VERSION 5.7 ;
  NOWIREEXTENSIONATPIN ON ;
  DIVIDERCHAR "/" ;
  BUSBITCHARS "[]" ;
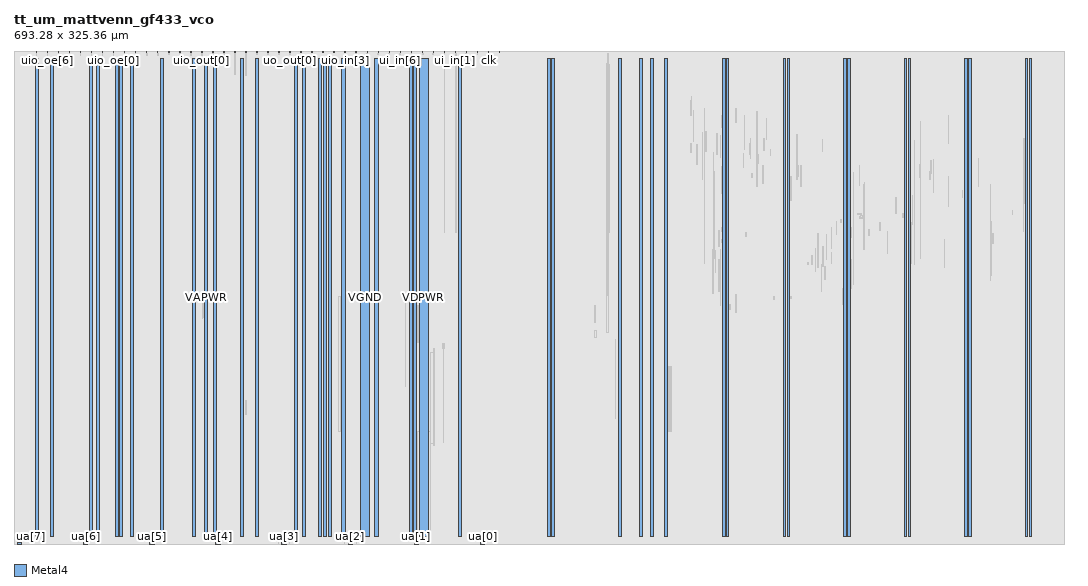
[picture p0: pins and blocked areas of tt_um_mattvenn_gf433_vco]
MACRO tt_um_mattvenn_gf433_vco
  CLASS BLOCK ;
  FOREIGN tt_um_mattvenn_gf433_vco ;
  ORIGIN 0.000 0.000 ;
  SIZE 693.280 BY 325.360 ;
  PIN clk
    DIRECTION INPUT ;
    USE SIGNAL ;
    PORT
      LAYER Metal4 ;
        RECT 313.170 324.360 313.470 325.360 ;
    END
  END clk
  PIN ena
    DIRECTION INPUT ;
    USE SIGNAL ;
    PORT
      LAYER Metal4 ;
        RECT 320.450 324.360 320.750 325.360 ;
    END
  END ena
  PIN rst_n
    DIRECTION INPUT ;
    USE SIGNAL ;
    PORT
      LAYER Metal4 ;
        RECT 305.890 324.360 306.190 325.360 ;
    END
  END rst_n
  PIN ua[0]
    DIRECTION INOUT ;
    USE SIGNAL ;
    PORT
      LAYER Metal4 ;
        RECT 307.900 0.000 310.900 1.000 ;
    END
  END ua[0]
  PIN ua[1]
    DIRECTION INOUT ;
    USE SIGNAL ;
    PORT
      LAYER Metal4 ;
        RECT 264.220 0.000 267.220 1.000 ;
    END
  END ua[1]
  PIN ua[2]
    DIRECTION INOUT ;
    USE SIGNAL ;
    PORT
      LAYER Metal4 ;
        RECT 220.540 0.000 223.540 1.000 ;
    END
  END ua[2]
  PIN ua[3]
    DIRECTION INOUT ;
    USE SIGNAL ;
    PORT
      LAYER Metal4 ;
        RECT 176.860 0.000 179.860 1.000 ;
    END
  END ua[3]
  PIN ua[4]
    DIRECTION INOUT ;
    USE SIGNAL ;
    PORT
      LAYER Metal4 ;
        RECT 133.180 0.000 136.180 1.000 ;
    END
  END ua[4]
  PIN ua[5]
    DIRECTION INOUT ;
    USE SIGNAL ;
    PORT
      LAYER Metal4 ;
        RECT 89.500 0.000 92.500 1.000 ;
    END
  END ua[5]
  PIN ua[6]
    DIRECTION INOUT ;
    USE SIGNAL ;
    PORT
      LAYER Metal4 ;
        RECT 45.820 0.000 48.820 1.000 ;
    END
  END ua[6]
  PIN ua[7]
    DIRECTION INOUT ;
    USE SIGNAL ;
    PORT
      LAYER Metal4 ;
        RECT 2.140 0.000 5.140 1.000 ;
    END
  END ua[7]
  PIN ui_in[0]
    DIRECTION INPUT ;
    USE SIGNAL ;
    PORT
      LAYER Metal4 ;
        RECT 298.610 324.360 298.910 325.360 ;
    END
  END ui_in[0]
  PIN ui_in[1]
    DIRECTION INPUT ;
    USE SIGNAL ;
    PORT
      LAYER Metal4 ;
        RECT 291.330 324.360 291.630 325.360 ;
    END
  END ui_in[1]
  PIN ui_in[2]
    DIRECTION INPUT ;
    USE SIGNAL ;
    PORT
      LAYER Metal4 ;
        RECT 284.050 324.360 284.350 325.360 ;
    END
  END ui_in[2]
  PIN ui_in[3]
    DIRECTION INPUT ;
    USE SIGNAL ;
    PORT
      LAYER Metal4 ;
        RECT 276.770 324.360 277.070 325.360 ;
    END
  END ui_in[3]
  PIN ui_in[4]
    DIRECTION INPUT ;
    USE SIGNAL ;
    PORT
      LAYER Metal4 ;
        RECT 269.490 324.360 269.790 325.360 ;
    END
  END ui_in[4]
  PIN ui_in[5]
    DIRECTION INPUT ;
    USE SIGNAL ;
    PORT
      LAYER Metal4 ;
        RECT 262.210 324.360 262.510 325.360 ;
    END
  END ui_in[5]
  PIN ui_in[6]
    DIRECTION INPUT ;
    USE SIGNAL ;
    PORT
      LAYER Metal4 ;
        RECT 254.930 324.360 255.230 325.360 ;
    END
  END ui_in[6]
  PIN ui_in[7]
    DIRECTION INPUT ;
    USE SIGNAL ;
    PORT
      LAYER Metal4 ;
        RECT 247.650 324.360 247.950 325.360 ;
    END
  END ui_in[7]
  PIN uio_in[0]
    DIRECTION INPUT ;
    USE SIGNAL ;
    PORT
      LAYER Metal4 ;
        RECT 240.370 324.360 240.670 325.360 ;
    END
  END uio_in[0]
  PIN uio_in[1]
    DIRECTION INPUT ;
    USE SIGNAL ;
    PORT
      LAYER Metal4 ;
        RECT 233.090 324.360 233.390 325.360 ;
    END
  END uio_in[1]
  PIN uio_in[2]
    DIRECTION INPUT ;
    USE SIGNAL ;
    PORT
      LAYER Metal4 ;
        RECT 225.810 324.360 226.110 325.360 ;
    END
  END uio_in[2]
  PIN uio_in[3]
    DIRECTION INPUT ;
    USE SIGNAL ;
    PORT
      LAYER Metal4 ;
        RECT 218.530 324.360 218.830 325.360 ;
    END
  END uio_in[3]
  PIN uio_in[4]
    DIRECTION INPUT ;
    USE SIGNAL ;
    PORT
      LAYER Metal4 ;
        RECT 211.250 324.360 211.550 325.360 ;
    END
  END uio_in[4]
  PIN uio_in[5]
    DIRECTION INPUT ;
    USE SIGNAL ;
    PORT
      LAYER Metal4 ;
        RECT 203.970 324.360 204.270 325.360 ;
    END
  END uio_in[5]
  PIN uio_in[6]
    DIRECTION INPUT ;
    USE SIGNAL ;
    PORT
      LAYER Metal4 ;
        RECT 196.690 324.360 196.990 325.360 ;
    END
  END uio_in[6]
  PIN uio_in[7]
    DIRECTION INPUT ;
    USE SIGNAL ;
    PORT
      LAYER Metal4 ;
        RECT 189.410 324.360 189.710 325.360 ;
    END
  END uio_in[7]
  PIN uio_oe[0]
    DIRECTION OUTPUT ;
    USE SIGNAL ;
    PORT
      LAYER Metal4 ;
        RECT 65.650 324.360 65.950 325.360 ;
    END
  END uio_oe[0]
  PIN uio_oe[1]
    DIRECTION OUTPUT ;
    USE SIGNAL ;
    PORT
      LAYER Metal4 ;
        RECT 58.370 324.360 58.670 325.360 ;
    END
  END uio_oe[1]
  PIN uio_oe[2]
    DIRECTION OUTPUT ;
    USE SIGNAL ;
    PORT
      LAYER Metal4 ;
        RECT 51.090 324.360 51.390 325.360 ;
    END
  END uio_oe[2]
  PIN uio_oe[3]
    DIRECTION OUTPUT ;
    USE SIGNAL ;
    PORT
      LAYER Metal4 ;
        RECT 43.810 324.360 44.110 325.360 ;
    END
  END uio_oe[3]
  PIN uio_oe[4]
    DIRECTION OUTPUT ;
    USE SIGNAL ;
    PORT
      LAYER Metal4 ;
        RECT 36.530 324.360 36.830 325.360 ;
    END
  END uio_oe[4]
  PIN uio_oe[5]
    DIRECTION OUTPUT ;
    USE SIGNAL ;
    PORT
      LAYER Metal4 ;
        RECT 29.250 324.360 29.550 325.360 ;
    END
  END uio_oe[5]
  PIN uio_oe[6]
    DIRECTION OUTPUT ;
    USE SIGNAL ;
    PORT
      LAYER Metal4 ;
        RECT 21.970 324.360 22.270 325.360 ;
    END
  END uio_oe[6]
  PIN uio_oe[7]
    DIRECTION OUTPUT ;
    USE SIGNAL ;
    PORT
      LAYER Metal4 ;
        RECT 14.690 324.360 14.990 325.360 ;
    END
  END uio_oe[7]
  PIN uio_out[0]
    DIRECTION OUTPUT ;
    USE SIGNAL ;
    PORT
      LAYER Metal4 ;
        RECT 123.890 324.360 124.190 325.360 ;
    END
  END uio_out[0]
  PIN uio_out[1]
    DIRECTION OUTPUT ;
    USE SIGNAL ;
    PORT
      LAYER Metal4 ;
        RECT 116.610 324.360 116.910 325.360 ;
    END
  END uio_out[1]
  PIN uio_out[2]
    DIRECTION OUTPUT ;
    USE SIGNAL ;
    PORT
      LAYER Metal4 ;
        RECT 109.330 324.360 109.630 325.360 ;
    END
  END uio_out[2]
  PIN uio_out[3]
    DIRECTION OUTPUT ;
    USE SIGNAL ;
    PORT
      LAYER Metal4 ;
        RECT 102.050 324.360 102.350 325.360 ;
    END
  END uio_out[3]
  PIN uio_out[4]
    DIRECTION OUTPUT ;
    USE SIGNAL ;
    PORT
      LAYER Metal4 ;
        RECT 94.770 324.360 95.070 325.360 ;
    END
  END uio_out[4]
  PIN uio_out[5]
    DIRECTION OUTPUT ;
    USE SIGNAL ;
    PORT
      LAYER Metal4 ;
        RECT 87.490 324.360 87.790 325.360 ;
    END
  END uio_out[5]
  PIN uio_out[6]
    DIRECTION OUTPUT ;
    USE SIGNAL ;
    PORT
      LAYER Metal4 ;
        RECT 80.210 324.360 80.510 325.360 ;
    END
  END uio_out[6]
  PIN uio_out[7]
    DIRECTION OUTPUT ;
    USE SIGNAL ;
    PORT
      LAYER Metal4 ;
        RECT 72.930 324.360 73.230 325.360 ;
    END
  END uio_out[7]
  PIN uo_out[0]
    DIRECTION OUTPUT ;
    USE SIGNAL ;
    PORT
      LAYER Metal4 ;
        RECT 182.130 324.360 182.430 325.360 ;
    END
  END uo_out[0]
  PIN uo_out[1]
    DIRECTION OUTPUT ;
    USE SIGNAL ;
    PORT
      LAYER Metal4 ;
        RECT 174.850 324.360 175.150 325.360 ;
    END
  END uo_out[1]
  PIN uo_out[2]
    DIRECTION OUTPUT ;
    USE SIGNAL ;
    PORT
      LAYER Metal4 ;
        RECT 167.570 324.360 167.870 325.360 ;
    END
  END uo_out[2]
  PIN uo_out[3]
    DIRECTION OUTPUT ;
    USE SIGNAL ;
    PORT
      LAYER Metal4 ;
        RECT 160.290 324.360 160.590 325.360 ;
    END
  END uo_out[3]
  PIN uo_out[4]
    DIRECTION OUTPUT ;
    USE SIGNAL ;
    PORT
      LAYER Metal4 ;
        RECT 153.010 324.360 153.310 325.360 ;
    END
  END uo_out[4]
  PIN uo_out[5]
    DIRECTION OUTPUT ;
    USE SIGNAL ;
    PORT
      LAYER Metal4 ;
        RECT 145.730 324.360 146.030 325.360 ;
    END
  END uo_out[5]
  PIN uo_out[6]
    DIRECTION OUTPUT ;
    USE SIGNAL ;
    PORT
      LAYER Metal4 ;
        RECT 138.450 324.360 138.750 325.360 ;
    END
  END uo_out[6]
  PIN uo_out[7]
    DIRECTION OUTPUT ;
    USE SIGNAL ;
    PORT
      LAYER Metal4 ;
        RECT 131.170 324.360 131.470 325.360 ;
    END
  END uo_out[7]
  PIN VDPWR
    DIRECTION INOUT ;
    USE POWER ;
    PORT
      LAYER Metal4 ;
        RECT 267.500 5.000 273.500 320.360 ;
    END
    PORT
      LAYER Metal4 ;
        RECT 470.480 5.000 472.080 320.360 ;
    END
    PORT
      LAYER Metal4 ;
        RECT 510.480 5.000 512.080 320.360 ;
    END
    PORT
      LAYER Metal4 ;
        RECT 550.480 5.000 552.080 320.360 ;
    END
    PORT
      LAYER Metal4 ;
        RECT 590.480 5.000 592.080 320.360 ;
    END
    PORT
      LAYER Metal4 ;
        RECT 630.480 5.000 632.080 320.360 ;
    END
    PORT
      LAYER Metal4 ;
        RECT 670.480 5.000 672.080 320.360 ;
    END
  END VDPWR
  PIN VAPWR
    DIRECTION INOUT ;
    USE POWER ;
    PORT
      LAYER Metal4 ;
        RECT 49.520 5.000 51.520 320.360 ;
    END
    PORT
      LAYER Metal4 ;
        RECT 66.880 5.000 68.880 320.360 ;
    END
    PORT
      LAYER Metal4 ;
        RECT 76.700 5.000 78.700 320.360 ;
    END
    PORT
      LAYER Metal4 ;
        RECT 118.100 5.000 120.100 320.360 ;
    END
    PORT
      LAYER Metal4 ;
        RECT 126.020 5.000 128.020 320.360 ;
    END
    PORT
      LAYER Metal4 ;
        RECT 185.360 5.000 187.360 320.360 ;
    END
    PORT
      LAYER Metal4 ;
        RECT 201.330 5.000 203.330 320.360 ;
    END
    PORT
      LAYER Metal4 ;
        RECT 207.410 5.000 209.410 320.360 ;
    END
    PORT
      LAYER Metal4 ;
        RECT 216.550 5.000 218.550 320.360 ;
    END
    PORT
      LAYER Metal4 ;
        RECT 260.900 5.000 262.900 320.360 ;
    END
    PORT
      LAYER Metal4 ;
        RECT 293.610 5.000 295.610 320.360 ;
    END
    PORT
      LAYER Metal4 ;
        RECT 351.990 5.000 353.990 320.360 ;
    END
    PORT
      LAYER Metal4 ;
        RECT 399.100 5.000 401.100 320.360 ;
    END
    PORT
      LAYER Metal4 ;
        RECT 429.480 5.000 431.480 320.360 ;
    END
  END VAPWR
  PIN VGND
    DIRECTION INOUT ;
    USE GROUND ;
    PORT
      LAYER Metal4 ;
        RECT 14.010 5.000 16.010 320.360 ;
    END
    PORT
      LAYER Metal4 ;
        RECT 23.790 5.000 25.790 320.360 ;
    END
    PORT
      LAYER Metal4 ;
        RECT 54.440 5.000 56.440 320.360 ;
    END
    PORT
      LAYER Metal4 ;
        RECT 69.880 5.000 71.880 320.360 ;
    END
    PORT
      LAYER Metal4 ;
        RECT 97.010 5.000 99.010 320.360 ;
    END
    PORT
      LAYER Metal4 ;
        RECT 131.670 5.000 133.670 320.360 ;
    END
    PORT
      LAYER Metal4 ;
        RECT 149.830 5.000 151.830 320.360 ;
    END
    PORT
      LAYER Metal4 ;
        RECT 159.630 5.000 161.630 320.360 ;
    END
    PORT
      LAYER Metal4 ;
        RECT 190.270 5.000 192.270 320.360 ;
    END
    PORT
      LAYER Metal4 ;
        RECT 204.330 5.000 206.330 320.360 ;
    END
    PORT
      LAYER Metal4 ;
        RECT 228.530 5.000 234.530 320.360 ;
    END
    PORT
      LAYER Metal4 ;
        RECT 238.350 5.000 240.350 320.360 ;
    END
    PORT
      LAYER Metal4 ;
        RECT 263.960 5.000 265.960 320.360 ;
    END
    PORT
      LAYER Metal4 ;
        RECT 354.990 5.000 356.990 320.360 ;
    END
    PORT
      LAYER Metal4 ;
        RECT 412.670 5.000 414.670 320.360 ;
    END
    PORT
      LAYER Metal4 ;
        RECT 420.510 5.000 422.510 320.360 ;
    END
    PORT
      LAYER Metal4 ;
        RECT 467.880 5.000 469.480 320.360 ;
    END
    PORT
      LAYER Metal4 ;
        RECT 507.880 5.000 509.480 320.360 ;
    END
    PORT
      LAYER Metal4 ;
        RECT 547.880 5.000 549.480 320.360 ;
    END
    PORT
      LAYER Metal4 ;
        RECT 587.880 5.000 589.480 320.360 ;
    END
    PORT
      LAYER Metal4 ;
        RECT 627.880 5.000 629.480 320.360 ;
    END
    PORT
      LAYER Metal4 ;
        RECT 667.880 5.000 669.480 320.360 ;
    END
  END VGND
  OBS
    LAYER Metal1 ;
      RECT 0.000 0.000 693.280 325.360 ;
    LAYER Metal2 ;
      RECT 0.000 0.000 693.280 325.360 ;
    LAYER Metal3 ;
      RECT 0.000 0.000 693.280 325.360 ;
    LAYER Metal4 ;
      RECT 501.660 161.290 501.940 163.350 ;
      RECT 512.860 161.850 513.140 163.350 ;
      RECT 214.010 74.610 215.750 163.390 ;
      RECT 476.460 152.890 476.740 164.470 ;
      RECT 547.020 157.930 547.300 168.950 ;
      RECT 466.380 157.370 466.660 194.150 ;
      RECT 391.490 139.890 392.550 317.070 ;
      RECT 533.020 166.890 533.300 184.630 ;
      RECT 524.060 184.250 524.340 185.750 ;
      RECT 465.260 166.890 465.540 187.990 ;
      RECT 552.620 168.570 552.900 187.990 ;
      RECT 526.860 184.250 527.140 190.790 ;
      RECT 539.740 185.370 540.020 192.470 ;
      RECT 463.020 179.210 463.300 193.590 ;
      RECT 535.820 175.290 536.100 181.270 ;
      RECT 461.340 165.210 461.620 194.710 ;
      RECT 529.100 179.770 529.380 195.270 ;
      RECT 534.140 183.130 534.420 196.390 ;
      RECT 466.940 198.810 467.220 200.870 ;
      RECT 614.220 182.570 614.500 200.870 ;
      RECT 536.380 187.610 536.660 204.230 ;
      RECT 530.780 182.570 531.060 204.790 ;
      RECT 646.140 198.250 646.420 204.790 ;
      RECT 483.180 203.290 483.460 205.910 ;
      RECT 576.700 191.530 576.980 206.470 ;
      RECT 465.260 196.570 465.540 207.030 ;
      RECT 564.380 203.850 564.660 207.590 ;
      RECT 539.740 194.890 540.020 208.710 ;
      RECT 552.620 202.170 552.900 208.710 ;
      RECT 466.940 206.090 467.220 209.270 ;
      RECT 571.660 207.210 571.940 212.070 ;
      RECT 592.380 185.370 592.660 212.070 ;
      RECT 543.100 204.410 543.380 212.630 ;
      RECT 645.020 176.970 645.300 213.190 ;
      RECT 545.900 212.250 546.180 214.310 ;
      RECT 558.220 214.610 560.740 216.550 ;
      RECT 558.780 215.610 560.180 217.110 ;
      RECT 557.100 217.290 559.620 218.230 ;
      RECT 586.780 215.610 587.060 218.230 ;
      RECT 659.020 217.290 659.300 220.470 ;
      RECT 666.300 206.650 666.580 226.070 ;
      RECT 582.300 218.410 582.580 228.870 ;
      RECT 592.940 211.130 593.220 229.990 ;
      RECT 625.980 228.490 626.260 233.350 ;
      RECT 561.020 194.330 561.300 237.270 ;
      RECT 644.460 174.170 644.740 237.270 ;
      RECT 561.580 208.890 561.860 238.950 ;
      RECT 512.860 226.810 513.140 242.870 ;
      RECT 617.020 222.890 617.300 242.870 ;
      RECT 487.100 241.930 487.380 244.550 ;
      RECT 554.300 171.370 554.580 245.110 ;
      RECT 462.460 188.730 462.740 245.670 ;
      RECT 604.700 240.810 604.980 245.670 ;
      RECT 466.940 231.290 467.220 249.030 ;
      RECT 517.900 242.490 518.180 249.590 ;
      RECT 519.580 236.330 519.860 249.590 ;
      RECT 558.220 236.890 558.500 249.590 ;
      RECT 494.380 238.010 494.660 250.150 ;
      RECT 597.980 241.930 598.260 250.710 ;
      RECT 605.260 244.730 605.540 252.950 ;
      RECT 606.940 231.850 607.220 254.070 ;
      RECT 636.620 236.330 636.900 254.630 ;
      RECT 491.580 251.450 491.860 256.870 ;
      RECT 481.500 248.650 481.780 257.990 ;
      RECT 461.900 173.050 462.180 258.550 ;
      RECT 499.420 256.490 499.700 260.230 ;
      RECT 450.700 250.330 450.980 263.590 ;
      RECT 485.420 257.050 485.700 264.150 ;
      RECT 446.780 258.730 447.060 264.710 ;
      RECT 594.620 184.810 594.900 266.390 ;
      RECT 533.580 259.290 533.860 266.950 ;
      RECT 485.980 254.250 486.260 267.510 ;
      RECT 494.940 259.850 495.220 267.510 ;
      RECT 666.860 224.570 667.140 267.510 ;
      RECT 466.380 255.370 466.660 269.750 ;
      RECT 516.780 240.810 517.060 270.310 ;
      RECT 464.140 257.050 464.420 270.870 ;
      RECT 454.620 240.810 454.900 271.990 ;
      RECT 456.860 259.290 457.140 272.550 ;
      RECT 598.540 188.730 598.820 278.710 ;
      RECT 496.620 267.130 496.900 280.950 ;
      RECT 466.940 274.970 467.220 283.190 ;
      RECT 482.060 260.410 482.340 283.190 ;
      RECT 617.020 264.330 617.300 283.190 ;
      RECT 490.460 236.330 490.740 285.430 ;
      RECT 448.460 266.010 448.740 285.990 ;
      RECT 455.740 185.370 456.020 287.670 ;
      RECT 476.460 278.330 476.740 287.670 ;
      RECT 446.780 282.810 447.060 292.710 ;
      RECT 447.340 292.890 447.620 295.510 ;
      RECT 392.850 205.850 393.230 316.390 ;
      RECT 535.260 174.730 535.540 182.950 ;
      RECT 392.170 164.370 392.550 323.870 ;
      RECT 14.650 322.310 15.030 324.060 ;
      RECT 21.930 322.310 22.310 324.060 ;
      RECT 29.210 322.310 29.590 324.060 ;
      RECT 36.490 322.310 36.870 324.060 ;
      RECT 43.770 322.310 44.150 324.060 ;
      RECT 51.050 322.310 51.430 324.060 ;
      RECT 58.330 322.310 58.710 324.060 ;
      RECT 65.610 322.310 65.990 324.060 ;
      RECT 72.890 322.310 73.270 324.060 ;
      RECT 80.170 322.310 80.550 324.060 ;
      RECT 87.450 322.310 87.830 324.060 ;
      RECT 94.730 322.310 95.110 324.060 ;
      RECT 101.810 323.490 102.390 324.060 ;
      RECT 109.290 322.310 109.670 324.060 ;
      RECT 116.570 322.310 116.950 324.060 ;
      RECT 123.850 322.310 124.230 324.060 ;
      RECT 131.130 322.310 131.510 324.060 ;
      RECT 138.410 322.310 138.790 324.060 ;
      RECT 145.690 309.890 146.390 324.060 ;
      RECT 152.810 309.210 153.350 324.060 ;
      RECT 160.250 323.490 160.670 324.060 ;
      RECT 167.530 323.490 168.150 324.060 ;
      RECT 174.570 323.490 175.190 324.060 ;
      RECT 182.050 323.490 182.470 324.060 ;
      RECT 225.570 323.490 226.150 324.060 ;
      RECT 233.050 323.490 233.430 324.060 ;
      RECT 240.330 323.490 240.910 324.060 ;
      RECT 247.330 323.490 247.990 324.060 ;
      RECT 254.810 323.490 255.270 324.060 ;
      RECT 262.170 323.490 262.670 324.060 ;
      RECT 269.450 323.490 270.150 324.060 ;
      RECT 276.570 323.490 277.110 324.060 ;
      RECT 284.010 205.850 284.430 324.060 ;
      RECT 291.290 205.850 291.910 324.060 ;
      RECT 298.330 323.490 298.950 324.060 ;
      RECT 305.810 323.490 306.230 324.060 ;
      RECT 313.130 323.490 313.670 324.060 ;
      RECT 283.370 67.130 283.750 132.110 ;
      RECT 284.050 129.010 284.430 132.110 ;
      RECT 266.370 133.090 266.750 157.270 ;
      RECT 258.210 103.850 258.590 160.670 ;
      RECT 124.250 148.730 124.630 162.030 ;
      RECT 124.930 149.410 125.310 162.030 ;
      RECT 89.500 1.300 92.500 1.550 ;
      RECT 133.180 1.300 136.180 1.550 ;
      RECT 307.900 1.300 310.900 2.230 ;
      RECT 218.040 0.000 226.040 2.245 ;
      RECT 264.220 1.300 265.960 4.700 ;
      RECT 174.360 0.000 181.730 6.045 ;
      RECT 266.370 3.890 274.910 74.310 ;
      RECT 152.810 85.490 153.190 94.710 ;
      RECT 275.210 66.450 276.950 126.670 ;
      RECT 277.250 65.090 277.630 129.390 ;
      RECT 282.690 129.010 283.070 132.110 ;
      RECT 432.290 74.610 432.670 117.150 ;
      RECT 432.970 74.610 433.350 117.150 ;
      RECT 396.930 82.770 397.310 134.830 ;
      RECT 383.330 136.490 384.390 140.950 ;
      RECT 433.650 74.610 434.030 117.150 ;
      RECT 383.330 146.010 383.710 157.270 ;
      RECT 472.540 155.130 472.820 158.310 ;
  END
END tt_um_mattvenn_gf433_vco
END LIBRARY
